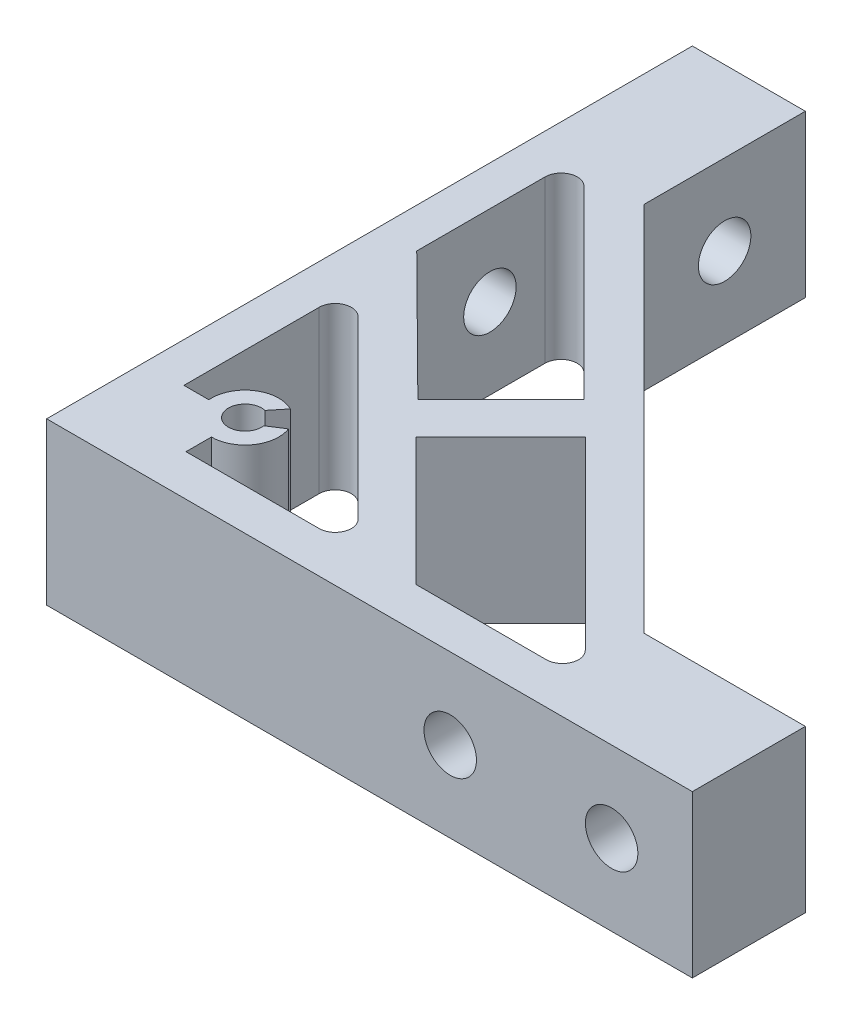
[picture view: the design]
ISO-10303-21;
HEADER;
FILE_DESCRIPTION(('STEP AP214'),'2;1');
FILE_NAME('part.step','',(''),(''),'','','');
FILE_SCHEMA(('AUTOMOTIVE_DESIGN { 1 0 10303 214 1 1 1 1 }'));
ENDSEC;
DATA;
#1=APPLICATION_CONTEXT('core data for automotive mechanical design processes');
#2=APPLICATION_PROTOCOL_DEFINITION('international standard','automotive_design',2000,#1);
#3=PRODUCT_CONTEXT('',#1,'mechanical');
#4=PRODUCT('Part','Part','',(#3));
#5=PRODUCT_RELATED_PRODUCT_CATEGORY('part','',(#4));
#6=PRODUCT_DEFINITION_FORMATION('','',#4);
#7=PRODUCT_DEFINITION_CONTEXT('part definition',#1,'design');
#8=PRODUCT_DEFINITION('design','',#6,#7);
#9=PRODUCT_DEFINITION_SHAPE('','',#8);
#10=(LENGTH_UNIT() NAMED_UNIT(*) SI_UNIT(.MILLI.,.METRE.));
#11=(NAMED_UNIT(*) PLANE_ANGLE_UNIT() SI_UNIT($,.RADIAN.));
#12=(NAMED_UNIT(*) SI_UNIT($,.STERADIAN.) SOLID_ANGLE_UNIT());
#13=UNCERTAINTY_MEASURE_WITH_UNIT(LENGTH_MEASURE(1.E-05),#10,'distance_accuracy_value','');
#14=(GEOMETRIC_REPRESENTATION_CONTEXT(3) GLOBAL_UNCERTAINTY_ASSIGNED_CONTEXT((#13)) GLOBAL_UNIT_ASSIGNED_CONTEXT((#10,
#11,#12)) REPRESENTATION_CONTEXT('',''));
#15=CARTESIAN_POINT('',(0.,0.,0.));
#16=DIRECTION('',(0.,0.,1.));
#17=DIRECTION('',(1.,0.,0.));
#18=AXIS2_PLACEMENT_3D('',#15,#16,#17);
#19=CARTESIAN_POINT('',(50.,10.,-80.));
#20=DIRECTION('',(0.,0.,1.));
#21=DIRECTION('',(1.,0.,0.));
#22=AXIS2_PLACEMENT_3D('',#19,#20,#21);
#23=CYLINDRICAL_SURFACE('',#22,3.25);
#24=CARTESIAN_POINT('',(50.,10.,-5.10542486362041));
#25=DIRECTION('',(0.,0.,1.));
#26=DIRECTION('',(1.,0.,0.));
#27=AXIS2_PLACEMENT_3D('',#24,#25,#26);
#28=CIRCLE('',#27,3.25);
#29=CARTESIAN_POINT('',(53.25,10.,-5.10542486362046));
#30=VERTEX_POINT('',#29);
#31=EDGE_CURVE('E368',#30,#30,#28,.F.);
#32=ORIENTED_EDGE('',*,*,#31,.T.);
#33=EDGE_LOOP('',(#32));
#34=FACE_BOUND('',#33,.T.);
#35=CARTESIAN_POINT('',(50.,10.,0.));
#36=DIRECTION('',(0.,0.,1.));
#37=DIRECTION('',(1.,0.,0.));
#38=AXIS2_PLACEMENT_3D('',#35,#36,#37);
#39=CIRCLE('',#38,3.25);
#40=CARTESIAN_POINT('',(53.25,10.,0.));
#41=VERTEX_POINT('',#40);
#42=EDGE_CURVE('E382',#41,#41,#39,.T.);
#43=ORIENTED_EDGE('',*,*,#42,.T.);
#44=EDGE_LOOP('',(#43));
#45=FACE_BOUND('',#44,.T.);
#46=ADVANCED_FACE('F41',(#34,#45),#23,.F.);
#47=CARTESIAN_POINT('',(14.,20.,-80.));
#48=DIRECTION('',(0.,0.,1.));
#49=DIRECTION('',(1.,0.,0.));
#50=AXIS2_PLACEMENT_3D('',#47,#48,#49);
#51=PLANE('',#50);
#52=DIRECTION('',(-1.,0.,0.));
#53=VECTOR('',#52,1.);
#54=CARTESIAN_POINT('',(14.,0.,-80.));
#55=LINE('',#54,#53);
#56=CARTESIAN_POINT('',(14.,0.,-80.));
#57=VERTEX_POINT('',#56);
#58=CARTESIAN_POINT('',(0.,0.,-80.));
#59=VERTEX_POINT('',#58);
#60=EDGE_CURVE('E408',#57,#59,#55,.T.);
#61=ORIENTED_EDGE('',*,*,#60,.T.);
#62=DIRECTION('',(0.,-1.,0.));
#63=VECTOR('',#62,1.);
#64=CARTESIAN_POINT('',(0.,20.,-80.));
#65=LINE('',#64,#63);
#66=CARTESIAN_POINT('',(0.,20.,-80.));
#67=VERTEX_POINT('',#66);
#68=EDGE_CURVE('E11',#67,#59,#65,.T.);
#69=ORIENTED_EDGE('',*,*,#68,.F.);
#70=DIRECTION('',(-1.,0.,0.));
#71=VECTOR('',#70,1.);
#72=CARTESIAN_POINT('',(14.,20.,-80.));
#73=LINE('',#72,#71);
#74=CARTESIAN_POINT('',(14.,20.,-80.));
#75=VERTEX_POINT('',#74);
#76=EDGE_CURVE('E395',#75,#67,#73,.T.);
#77=ORIENTED_EDGE('',*,*,#76,.F.);
#78=DIRECTION('',(0.,-1.,0.));
#79=VECTOR('',#78,1.);
#80=CARTESIAN_POINT('',(14.,20.,-80.));
#81=LINE('',#80,#79);
#82=EDGE_CURVE('E410',#75,#57,#81,.T.);
#83=ORIENTED_EDGE('',*,*,#82,.T.);
#84=EDGE_LOOP('',(#61,#69,#77,#83));
#85=FACE_BOUND('',#84,.T.);
#86=ADVANCED_FACE('F43',(#85),#51,.F.);
#87=CARTESIAN_POINT('',(0.,20.,-80.));
#88=DIRECTION('',(1.,0.,0.));
#89=DIRECTION('',(0.,0.,-1.));
#90=AXIS2_PLACEMENT_3D('',#87,#88,#89);
#91=PLANE('',#90);
#92=CARTESIAN_POINT('',(0.,9.99999999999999,-70.));
#93=DIRECTION('',(-1.,0.,0.));
#94=DIRECTION('',(0.,0.,1.));
#95=AXIS2_PLACEMENT_3D('',#92,#93,#94);
#96=CIRCLE('',#95,3.25000000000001);
#97=CARTESIAN_POINT('',(0.,9.99999999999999,-66.75));
#98=VERTEX_POINT('',#97);
#99=EDGE_CURVE('E383',#98,#98,#96,.T.);
#100=ORIENTED_EDGE('',*,*,#99,.F.);
#101=EDGE_LOOP('',(#100));
#102=FACE_BOUND('',#101,.T.);
#103=CARTESIAN_POINT('',(0.,9.99999999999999,-50.));
#104=DIRECTION('',(-1.,0.,0.));
#105=DIRECTION('',(0.,0.,1.));
#106=AXIS2_PLACEMENT_3D('',#103,#104,#105);
#107=CIRCLE('',#106,3.25);
#108=CARTESIAN_POINT('',(0.,9.99999999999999,-46.75));
#109=VERTEX_POINT('',#108);
#110=EDGE_CURVE('E388',#109,#109,#107,.T.);
#111=ORIENTED_EDGE('',*,*,#110,.F.);
#112=EDGE_LOOP('',(#111));
#113=FACE_BOUND('',#112,.T.);
#114=DIRECTION('',(0.,0.,1.));
#115=VECTOR('',#114,1.);
#116=CARTESIAN_POINT('',(0.,0.,-80.));
#117=LINE('',#116,#115);
#118=CARTESIAN_POINT('',(0.,0.,0.));
#119=VERTEX_POINT('',#118);
#120=EDGE_CURVE('E415',#59,#119,#117,.T.);
#121=ORIENTED_EDGE('',*,*,#120,.T.);
#122=DIRECTION('',(0.,-1.,0.));
#123=VECTOR('',#122,1.);
#124=CARTESIAN_POINT('',(0.,20.,0.));
#125=LINE('',#124,#123);
#126=CARTESIAN_POINT('',(0.,20.,0.));
#127=VERTEX_POINT('',#126);
#128=EDGE_CURVE('E49',#127,#119,#125,.T.);
#129=ORIENTED_EDGE('',*,*,#128,.F.);
#130=DIRECTION('',(0.,0.,1.));
#131=VECTOR('',#130,1.);
#132=CARTESIAN_POINT('',(0.,20.,-80.));
#133=LINE('',#132,#131);
#134=EDGE_CURVE('E394',#67,#127,#133,.T.);
#135=ORIENTED_EDGE('',*,*,#134,.F.);
#136=ORIENTED_EDGE('',*,*,#68,.T.);
#137=EDGE_LOOP('',(#121,#129,#135,#136));
#138=FACE_BOUND('',#137,.T.);
#139=ADVANCED_FACE('F533',(#102,#113,#138),#91,.F.);
#140=CARTESIAN_POINT('',(0.,20.,0.));
#141=DIRECTION('',(0.,0.,-1.));
#142=DIRECTION('',(-1.,0.,0.));
#143=AXIS2_PLACEMENT_3D('',#140,#141,#142);
#144=PLANE('',#143);
#145=CARTESIAN_POINT('',(70.,10.,0.));
#146=DIRECTION('',(0.,0.,1.));
#147=DIRECTION('',(1.,0.,0.));
#148=AXIS2_PLACEMENT_3D('',#145,#146,#147);
#149=CIRCLE('',#148,3.25000000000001);
#150=CARTESIAN_POINT('',(73.25,10.,0.));
#151=VERTEX_POINT('',#150);
#152=EDGE_CURVE('E380',#151,#151,#149,.T.);
#153=ORIENTED_EDGE('',*,*,#152,.F.);
#154=EDGE_LOOP('',(#153));
#155=FACE_BOUND('',#154,.T.);
#156=ORIENTED_EDGE('',*,*,#42,.F.);
#157=EDGE_LOOP('',(#156));
#158=FACE_BOUND('',#157,.T.);
#159=DIRECTION('',(1.,0.,0.));
#160=VECTOR('',#159,1.);
#161=CARTESIAN_POINT('',(0.,0.,0.));
#162=LINE('',#161,#160);
#163=CARTESIAN_POINT('',(80.,0.,0.));
#164=VERTEX_POINT('',#163);
#165=EDGE_CURVE('E413',#119,#164,#162,.T.);
#166=ORIENTED_EDGE('',*,*,#165,.T.);
#167=DIRECTION('',(0.,-1.,0.));
#168=VECTOR('',#167,1.);
#169=CARTESIAN_POINT('',(80.,20.,0.));
#170=LINE('',#169,#168);
#171=CARTESIAN_POINT('',(80.,20.,0.));
#172=VERTEX_POINT('',#171);
#173=EDGE_CURVE('E432',#172,#164,#170,.T.);
#174=ORIENTED_EDGE('',*,*,#173,.F.);
#175=DIRECTION('',(1.,0.,0.));
#176=VECTOR('',#175,1.);
#177=CARTESIAN_POINT('',(0.,20.,0.));
#178=LINE('',#177,#176);
#179=EDGE_CURVE('E400',#127,#172,#178,.T.);
#180=ORIENTED_EDGE('',*,*,#179,.F.);
#181=ORIENTED_EDGE('',*,*,#128,.T.);
#182=EDGE_LOOP('',(#166,#174,#180,#181));
#183=FACE_BOUND('',#182,.T.);
#184=ADVANCED_FACE('F567',(#155,#158,#183),#144,.F.);
#185=CARTESIAN_POINT('',(80.,20.,0.));
#186=DIRECTION('',(-1.,0.,0.));
#187=DIRECTION('',(0.,0.,1.));
#188=AXIS2_PLACEMENT_3D('',#185,#186,#187);
#189=PLANE('',#188);
#190=DIRECTION('',(0.,0.,-1.));
#191=VECTOR('',#190,1.);
#192=CARTESIAN_POINT('',(80.,0.,0.));
#193=LINE('',#192,#191);
#194=CARTESIAN_POINT('',(80.,0.,-14.));
#195=VERTEX_POINT('',#194);
#196=EDGE_CURVE('E417',#164,#195,#193,.T.);
#197=ORIENTED_EDGE('',*,*,#196,.T.);
#198=DIRECTION('',(0.,-1.,0.));
#199=VECTOR('',#198,1.);
#200=CARTESIAN_POINT('',(80.,20.,-14.));
#201=LINE('',#200,#199);
#202=CARTESIAN_POINT('',(80.,20.,-14.));
#203=VERTEX_POINT('',#202);
#204=EDGE_CURVE('E431',#203,#195,#201,.T.);
#205=ORIENTED_EDGE('',*,*,#204,.F.);
#206=DIRECTION('',(0.,0.,-1.));
#207=VECTOR('',#206,1.);
#208=CARTESIAN_POINT('',(80.,20.,0.));
#209=LINE('',#208,#207);
#210=EDGE_CURVE('E398',#172,#203,#209,.T.);
#211=ORIENTED_EDGE('',*,*,#210,.F.);
#212=ORIENTED_EDGE('',*,*,#173,.T.);
#213=EDGE_LOOP('',(#197,#205,#211,#212));
#214=FACE_BOUND('',#213,.T.);
#215=ADVANCED_FACE('F564',(#214),#189,.F.);
#216=CARTESIAN_POINT('',(80.,20.,-14.));
#217=DIRECTION('',(0.,0.,1.));
#218=DIRECTION('',(1.,0.,0.));
#219=AXIS2_PLACEMENT_3D('',#216,#217,#218);
#220=PLANE('',#219);
#221=CARTESIAN_POINT('',(70.,10.,-14.));
#222=DIRECTION('',(0.,0.,1.));
#223=DIRECTION('',(1.,0.,0.));
#224=AXIS2_PLACEMENT_3D('',#221,#222,#223);
#225=CIRCLE('',#224,3.25000000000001);
#226=CARTESIAN_POINT('',(73.25,10.,-14.));
#227=VERTEX_POINT('',#226);
#228=EDGE_CURVE('E379',#227,#227,#225,.T.);
#229=ORIENTED_EDGE('',*,*,#228,.T.);
#230=EDGE_LOOP('',(#229));
#231=FACE_BOUND('',#230,.T.);
#232=DIRECTION('',(-1.,0.,0.));
#233=VECTOR('',#232,1.);
#234=CARTESIAN_POINT('',(80.,0.,-14.));
#235=LINE('',#234,#233);
#236=CARTESIAN_POINT('',(60.,0.,-14.));
#237=VERTEX_POINT('',#236);
#238=EDGE_CURVE('E420',#195,#237,#235,.T.);
#239=ORIENTED_EDGE('',*,*,#238,.T.);
#240=DIRECTION('',(0.,-1.,0.));
#241=VECTOR('',#240,1.);
#242=CARTESIAN_POINT('',(60.,20.,-14.));
#243=LINE('',#242,#241);
#244=CARTESIAN_POINT('',(60.,20.,-14.));
#245=VERTEX_POINT('',#244);
#246=EDGE_CURVE('E426',#245,#237,#243,.T.);
#247=ORIENTED_EDGE('',*,*,#246,.F.);
#248=DIRECTION('',(-1.,0.,0.));
#249=VECTOR('',#248,1.);
#250=CARTESIAN_POINT('',(80.,20.,-14.));
#251=LINE('',#250,#249);
#252=EDGE_CURVE('E405',#203,#245,#251,.T.);
#253=ORIENTED_EDGE('',*,*,#252,.F.);
#254=ORIENTED_EDGE('',*,*,#204,.T.);
#255=EDGE_LOOP('',(#239,#247,#253,#254));
#256=FACE_BOUND('',#255,.T.);
#257=ADVANCED_FACE('F565',(#231,#256),#220,.F.);
#258=CARTESIAN_POINT('',(60.,20.,-14.));
#259=DIRECTION('',(-0.707106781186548,0.,0.707106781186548));
#260=DIRECTION('',(0.707106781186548,0.,0.707106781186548));
#261=AXIS2_PLACEMENT_3D('',#258,#259,#260);
#262=PLANE('',#261);
#263=CARTESIAN_POINT('',(24.,9.99999999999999,-50.));
#264=DIRECTION('',(-0.707106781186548,0.,0.707106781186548));
#265=DIRECTION('',(0.707106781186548,0.,0.707106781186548));
#266=AXIS2_PLACEMENT_3D('',#263,#264,#265);
#267=ELLIPSE('',#266,7.77817459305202,5.5);
#268=CARTESIAN_POINT('',(29.5,9.99999999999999,-44.5));
#269=VERTEX_POINT('',#268);
#270=EDGE_CURVE('E449',#269,#269,#267,.T.);
#271=ORIENTED_EDGE('',*,*,#270,.T.);
#272=EDGE_LOOP('',(#271));
#273=FACE_BOUND('',#272,.T.);
#274=CARTESIAN_POINT('',(50.,10.,-24.));
#275=DIRECTION('',(-0.707106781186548,0.,0.707106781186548));
#276=DIRECTION('',(-0.707106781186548,0.,-0.707106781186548));
#277=AXIS2_PLACEMENT_3D('',#274,#275,#276);
#278=ELLIPSE('',#277,7.77817459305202,5.5);
#279=CARTESIAN_POINT('',(44.5,10.,-29.5));
#280=VERTEX_POINT('',#279);
#281=EDGE_CURVE('E244',#280,#280,#278,.F.);
#282=ORIENTED_EDGE('',*,*,#281,.F.);
#283=EDGE_LOOP('',(#282));
#284=FACE_BOUND('',#283,.T.);
#285=DIRECTION('',(-0.707106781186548,0.,-0.707106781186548));
#286=VECTOR('',#285,1.);
#287=CARTESIAN_POINT('',(60.,0.,-14.));
#288=LINE('',#287,#286);
#289=CARTESIAN_POINT('',(14.,0.,-60.));
#290=VERTEX_POINT('',#289);
#291=EDGE_CURVE('E418',#237,#290,#288,.T.);
#292=ORIENTED_EDGE('',*,*,#291,.T.);
#293=DIRECTION('',(0.,-1.,0.));
#294=VECTOR('',#293,1.);
#295=CARTESIAN_POINT('',(14.,20.,-60.));
#296=LINE('',#295,#294);
#297=CARTESIAN_POINT('',(14.,20.,-60.));
#298=VERTEX_POINT('',#297);
#299=EDGE_CURVE('E424',#298,#290,#296,.T.);
#300=ORIENTED_EDGE('',*,*,#299,.F.);
#301=DIRECTION('',(-0.707106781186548,0.,-0.707106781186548));
#302=VECTOR('',#301,1.);
#303=CARTESIAN_POINT('',(60.,20.,-14.));
#304=LINE('',#303,#302);
#305=EDGE_CURVE('E404',#245,#298,#304,.T.);
#306=ORIENTED_EDGE('',*,*,#305,.F.);
#307=ORIENTED_EDGE('',*,*,#246,.T.);
#308=EDGE_LOOP('',(#292,#300,#306,#307));
#309=FACE_BOUND('',#308,.T.);
#310=ADVANCED_FACE('F556',(#273,#284,#309),#262,.F.);
#311=CARTESIAN_POINT('',(14.,20.,-60.));
#312=DIRECTION('',(-1.,0.,0.));
#313=DIRECTION('',(0.,0.,1.));
#314=AXIS2_PLACEMENT_3D('',#311,#312,#313);
#315=PLANE('',#314);
#316=CARTESIAN_POINT('',(14.,9.99999999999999,-70.));
#317=DIRECTION('',(-1.,0.,0.));
#318=DIRECTION('',(0.,0.,1.));
#319=AXIS2_PLACEMENT_3D('',#316,#317,#318);
#320=CIRCLE('',#319,3.25000000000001);
#321=CARTESIAN_POINT('',(14.,9.99999999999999,-66.75));
#322=VERTEX_POINT('',#321);
#323=EDGE_CURVE('E390',#322,#322,#320,.T.);
#324=ORIENTED_EDGE('',*,*,#323,.T.);
#325=EDGE_LOOP('',(#324));
#326=FACE_BOUND('',#325,.T.);
#327=DIRECTION('',(0.,0.,-1.));
#328=VECTOR('',#327,1.);
#329=CARTESIAN_POINT('',(14.,0.,-60.));
#330=LINE('',#329,#328);
#331=EDGE_CURVE('E397',#290,#57,#330,.T.);
#332=ORIENTED_EDGE('',*,*,#331,.T.);
#333=ORIENTED_EDGE('',*,*,#82,.F.);
#334=DIRECTION('',(0.,0.,-1.));
#335=VECTOR('',#334,1.);
#336=CARTESIAN_POINT('',(14.,20.,-60.));
#337=LINE('',#336,#335);
#338=EDGE_CURVE('E409',#298,#75,#337,.T.);
#339=ORIENTED_EDGE('',*,*,#338,.F.);
#340=ORIENTED_EDGE('',*,*,#299,.T.);
#341=EDGE_LOOP('',(#332,#333,#339,#340));
#342=FACE_BOUND('',#341,.T.);
#343=ADVANCED_FACE('F553',(#326,#342),#315,.F.);
#344=CARTESIAN_POINT('',(0.,20.,0.));
#345=DIRECTION('',(0.,1.,0.));
#346=DIRECTION('',(0.,0.,1.));
#347=AXIS2_PLACEMENT_3D('',#344,#345,#346);
#348=PLANE('',#347);
#349=DIRECTION('',(-0.707106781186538,0.,-0.707106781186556));
#350=VECTOR('',#349,1.);
#351=CARTESIAN_POINT('',(40.6627812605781,20.,-5.10542486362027));
#352=LINE('',#351,#350);
#353=CARTESIAN_POINT('',(40.6627812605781,20.,-5.10542486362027));
#354=VERTEX_POINT('',#353);
#355=CARTESIAN_POINT('',(24.8379244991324,20.,-20.9302816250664));
#356=VERTEX_POINT('',#355);
#357=EDGE_CURVE('E313',#354,#356,#352,.T.);
#358=ORIENTED_EDGE('',*,*,#357,.T.);
#359=DIRECTION('',(0.707106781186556,0.,-0.707106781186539));
#360=VECTOR('',#359,1.);
#361=CARTESIAN_POINT('',(24.8379244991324,20.,-20.9302816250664));
#362=LINE('',#361,#360);
#363=CARTESIAN_POINT('',(35.3190252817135,20.,-31.4113824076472));
#364=VERTEX_POINT('',#363);
#365=EDGE_CURVE('E334',#356,#364,#362,.T.);
#366=ORIENTED_EDGE('',*,*,#365,.T.);
#367=DIRECTION('',(0.707106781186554,0.,0.707106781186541));
#368=VECTOR('',#367,1.);
#369=CARTESIAN_POINT('',(35.3190252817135,20.,-31.4113824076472));
#370=LINE('',#369,#368);
#371=CARTESIAN_POINT('',(58.2107692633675,20.,-8.51963842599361));
#372=VERTEX_POINT('',#371);
#373=EDGE_CURVE('E59',#364,#372,#370,.T.);
#374=ORIENTED_EDGE('',*,*,#373,.T.);
#375=CARTESIAN_POINT('',(56.7965557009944,20.,-7.10542486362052));
#376=DIRECTION('',(0.,-1.,0.));
#377=DIRECTION('',(0.,0.,-1.));
#378=AXIS2_PLACEMENT_3D('',#375,#376,#377);
#379=CIRCLE('',#378,2.);
#380=CARTESIAN_POINT('',(56.7965557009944,20.,-5.10542486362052));
#381=VERTEX_POINT('',#380);
#382=EDGE_CURVE('E327',#372,#381,#379,.T.);
#383=ORIENTED_EDGE('',*,*,#382,.T.);
#384=DIRECTION('',(-1.,0.,0.));
#385=VECTOR('',#384,1.);
#386=CARTESIAN_POINT('',(56.7965557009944,20.,-5.10542486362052));
#387=LINE('',#386,#385);
#388=EDGE_CURVE('E302',#381,#354,#387,.T.);
#389=ORIENTED_EDGE('',*,*,#388,.T.);
#390=EDGE_LOOP('',(#358,#366,#374,#383,#389));
#391=FACE_BOUND('',#390,.T.);
#392=DIRECTION('',(0.,0.,-1.));
#393=VECTOR('',#392,1.);
#394=CARTESIAN_POINT('',(12.1608269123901,20.,-5.10542486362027));
#395=LINE('',#394,#393);
#396=CARTESIAN_POINT('',(12.1608269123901,20.,-5.10542486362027));
#397=VERTEX_POINT('',#396);
#398=CARTESIAN_POINT('',(12.1608269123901,20.,-8.24916747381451));
#399=VERTEX_POINT('',#398);
#400=EDGE_CURVE('E239',#397,#399,#395,.T.);
#401=ORIENTED_EDGE('',*,*,#400,.T.);
#402=CARTESIAN_POINT('',(12.1608269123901,20.,-12.4227167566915));
#403=DIRECTION('',(0.,1.,0.));
#404=DIRECTION('',(0.,0.,-1.));
#405=AXIS2_PLACEMENT_3D('',#402,#403,#404);
#406=CIRCLE('',#405,4.17354928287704);
#407=CARTESIAN_POINT('',(16.0655128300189,20.,-13.8964675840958));
#408=VERTEX_POINT('',#407);
#409=EDGE_CURVE('E300',#399,#408,#406,.T.);
#410=ORIENTED_EDGE('',*,*,#409,.T.);
#411=DIRECTION('',(-0.841480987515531,0.,0.540286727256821));
#412=VECTOR('',#411,1.);
#413=CARTESIAN_POINT('',(16.0655128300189,20.,-13.8964675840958));
#414=LINE('',#413,#412);
#415=CARTESIAN_POINT('',(14.2026570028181,20.,-12.7003903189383));
#416=VERTEX_POINT('',#415);
#417=EDGE_CURVE('E66',#408,#416,#414,.T.);
#418=ORIENTED_EDGE('',*,*,#417,.T.);
#419=CARTESIAN_POINT('',(12.1608269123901,20.,-12.4227167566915));
#420=DIRECTION('',(0.,-1.,0.));
#421=DIRECTION('',(0.,0.,-1.));
#422=AXIS2_PLACEMENT_3D('',#419,#420,#421);
#423=CIRCLE('',#422,2.06062435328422);
#424=CARTESIAN_POINT('',(12.6254849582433,20.,-14.4302689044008));
#425=VERTEX_POINT('',#424);
#426=EDGE_CURVE('E291',#416,#425,#423,.T.);
#427=ORIENTED_EDGE('',*,*,#426,.T.);
#428=DIRECTION('',(0.631646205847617,0.,-0.775256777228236));
#429=VECTOR('',#428,1.);
#430=CARTESIAN_POINT('',(12.6254849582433,20.,-14.4302689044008));
#431=LINE('',#430,#429);
#432=CARTESIAN_POINT('',(14.030107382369,20.,-16.1542451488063));
#433=VERTEX_POINT('',#432);
#434=EDGE_CURVE('E288',#425,#433,#431,.T.);
#435=ORIENTED_EDGE('',*,*,#434,.T.);
#436=CARTESIAN_POINT('',(12.1608269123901,20.,-12.4227167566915));
#437=DIRECTION('',(0.,1.,0.));
#438=DIRECTION('',(0.,0.,-1.));
#439=AXIS2_PLACEMENT_3D('',#436,#437,#438);
#440=CIRCLE('',#439,4.17354928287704);
#441=CARTESIAN_POINT('',(8.00052028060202,20.,-12.0905084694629));
#442=VERTEX_POINT('',#441);
#443=EDGE_CURVE('E289',#433,#442,#440,.T.);
#444=ORIENTED_EDGE('',*,*,#443,.T.);
#445=DIRECTION('',(-1.,0.,0.));
#446=VECTOR('',#445,1.);
#447=CARTESIAN_POINT('',(4.91656822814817,20.,-12.0905084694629));
#448=LINE('',#447,#446);
#449=CARTESIAN_POINT('',(4.91656822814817,20.,-12.0905084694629));
#450=VERTEX_POINT('',#449);
#451=EDGE_CURVE('E283',#442,#450,#448,.T.);
#452=ORIENTED_EDGE('',*,*,#451,.T.);
#453=DIRECTION('',(0.,0.,-1.));
#454=VECTOR('',#453,1.);
#455=CARTESIAN_POINT('',(4.91656822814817,20.,-28.8402167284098));
#456=LINE('',#455,#454);
#457=CARTESIAN_POINT('',(4.91656822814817,20.,-28.8402167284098));
#458=VERTEX_POINT('',#457);
#459=EDGE_CURVE('E281',#450,#458,#456,.T.);
#460=ORIENTED_EDGE('',*,*,#459,.T.);
#461=CARTESIAN_POINT('',(6.91656822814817,20.,-28.8402167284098));
#462=DIRECTION('',(0.,-1.,0.));
#463=DIRECTION('',(0.,0.,1.));
#464=AXIS2_PLACEMENT_3D('',#461,#462,#463);
#465=CIRCLE('',#464,2.);
#466=CARTESIAN_POINT('',(8.33078179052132,20.,-30.2544302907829));
#467=VERTEX_POINT('',#466);
#468=EDGE_CURVE('E280',#458,#467,#465,.T.);
#469=ORIENTED_EDGE('',*,*,#468,.T.);
#470=DIRECTION('',(0.707106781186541,0.,0.707106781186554));
#471=VECTOR('',#470,1.);
#472=CARTESIAN_POINT('',(30.0655736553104,20.,-8.51963842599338));
#473=LINE('',#472,#471);
#474=CARTESIAN_POINT('',(30.0655736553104,20.,-8.51963842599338));
#475=VERTEX_POINT('',#474);
#476=EDGE_CURVE('E273',#467,#475,#473,.T.);
#477=ORIENTED_EDGE('',*,*,#476,.T.);
#478=CARTESIAN_POINT('',(28.6513600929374,20.,-7.10542486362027));
#479=DIRECTION('',(0.,-1.,0.));
#480=DIRECTION('',(0.,0.,1.));
#481=AXIS2_PLACEMENT_3D('',#478,#479,#480);
#482=CIRCLE('',#481,2.);
#483=CARTESIAN_POINT('',(28.6513600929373,20.,-5.10542486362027));
#484=VERTEX_POINT('',#483);
#485=EDGE_CURVE('E272',#475,#484,#482,.T.);
#486=ORIENTED_EDGE('',*,*,#485,.T.);
#487=DIRECTION('',(-1.,0.,0.));
#488=VECTOR('',#487,1.);
#489=CARTESIAN_POINT('',(12.1608269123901,20.,-5.10542486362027));
#490=LINE('',#489,#488);
#491=EDGE_CURVE('E266',#484,#397,#490,.T.);
#492=ORIENTED_EDGE('',*,*,#491,.T.);
#493=EDGE_LOOP('',(#401,#410,#418,#427,#435,#444,#452,#460,#469,#477,#486,#492));
#494=FACE_BOUND('',#493,.T.);
#495=DIRECTION('',(-0.710210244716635,0.,-0.703989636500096));
#496=VECTOR('',#495,1.);
#497=CARTESIAN_POINT('',(4.91656822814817,20.,-40.9348925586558));
#498=LINE('',#497,#496);
#499=CARTESIAN_POINT('',(20.90108039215,20.,-25.0903859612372));
#500=VERTEX_POINT('',#499);
#501=CARTESIAN_POINT('',(4.91656822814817,20.,-40.9348925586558));
#502=VERTEX_POINT('',#501);
#503=EDGE_CURVE('E340',#500,#502,#498,.T.);
#504=ORIENTED_EDGE('',*,*,#503,.T.);
#505=DIRECTION('',(0.,0.,-1.));
#506=VECTOR('',#505,1.);
#507=CARTESIAN_POINT('',(4.91656822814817,20.,-56.8281788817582));
#508=LINE('',#507,#506);
#509=CARTESIAN_POINT('',(4.91656822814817,20.,-56.8281788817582));
#510=VERTEX_POINT('',#509);
#511=EDGE_CURVE('E338',#502,#510,#508,.T.);
#512=ORIENTED_EDGE('',*,*,#511,.T.);
#513=CARTESIAN_POINT('',(6.91656822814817,20.,-56.8281788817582));
#514=DIRECTION('',(0.,-1.,0.));
#515=DIRECTION('',(0.,0.,1.));
#516=AXIS2_PLACEMENT_3D('',#513,#514,#515);
#517=CIRCLE('',#516,2.);
#518=CARTESIAN_POINT('',(8.33078179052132,20.,-58.2423924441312));
#519=VERTEX_POINT('',#518);
#520=EDGE_CURVE('E343',#510,#519,#517,.T.);
#521=ORIENTED_EDGE('',*,*,#520,.T.);
#522=DIRECTION('',(0.707106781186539,0.,0.707106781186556));
#523=VECTOR('',#522,1.);
#524=CARTESIAN_POINT('',(31.1919343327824,20.,-35.3812399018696));
#525=LINE('',#524,#523);
#526=CARTESIAN_POINT('',(31.1919343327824,20.,-35.3812399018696));
#527=VERTEX_POINT('',#526);
#528=EDGE_CURVE('E350',#519,#527,#525,.T.);
#529=ORIENTED_EDGE('',*,*,#528,.T.);
#530=DIRECTION('',(-0.707106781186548,0.,0.707106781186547));
#531=VECTOR('',#530,1.);
#532=CARTESIAN_POINT('',(20.90108039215,20.,-25.0903859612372));
#533=LINE('',#532,#531);
#534=EDGE_CURVE('E349',#527,#500,#533,.T.);
#535=ORIENTED_EDGE('',*,*,#534,.T.);
#536=EDGE_LOOP('',(#504,#512,#521,#529,#535));
#537=FACE_BOUND('',#536,.T.);
#538=ORIENTED_EDGE('',*,*,#76,.T.);
#539=ORIENTED_EDGE('',*,*,#134,.T.);
#540=ORIENTED_EDGE('',*,*,#179,.T.);
#541=ORIENTED_EDGE('',*,*,#210,.T.);
#542=ORIENTED_EDGE('',*,*,#252,.T.);
#543=ORIENTED_EDGE('',*,*,#305,.T.);
#544=ORIENTED_EDGE('',*,*,#338,.T.);
#545=EDGE_LOOP('',(#538,#539,#540,#541,#542,#543,#544));
#546=FACE_BOUND('',#545,.T.);
#547=ADVANCED_FACE('F509',(#391,#494,#537,#546),#348,.T.);
#548=CARTESIAN_POINT('',(0.,0.,0.));
#549=DIRECTION('',(0.,1.,0.));
#550=DIRECTION('',(0.,0.,1.));
#551=AXIS2_PLACEMENT_3D('',#548,#549,#550);
#552=PLANE('',#551);
#553=DIRECTION('',(0.707106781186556,0.,-0.707106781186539));
#554=VECTOR('',#553,1.);
#555=CARTESIAN_POINT('',(24.8379244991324,0.,-20.9302816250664));
#556=LINE('',#555,#554);
#557=CARTESIAN_POINT('',(24.8379244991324,0.,-20.9302816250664));
#558=VERTEX_POINT('',#557);
#559=CARTESIAN_POINT('',(35.3190252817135,0.,-31.4113824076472));
#560=VERTEX_POINT('',#559);
#561=EDGE_CURVE('E318',#558,#560,#556,.T.);
#562=ORIENTED_EDGE('',*,*,#561,.F.);
#563=DIRECTION('',(-0.707106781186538,0.,-0.707106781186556));
#564=VECTOR('',#563,1.);
#565=CARTESIAN_POINT('',(40.6627812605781,0.,-5.10542486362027));
#566=LINE('',#565,#564);
#567=CARTESIAN_POINT('',(40.6627812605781,0.,-5.10542486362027));
#568=VERTEX_POINT('',#567);
#569=EDGE_CURVE('E325',#568,#558,#566,.T.);
#570=ORIENTED_EDGE('',*,*,#569,.F.);
#571=DIRECTION('',(-1.,0.,0.));
#572=VECTOR('',#571,1.);
#573=CARTESIAN_POINT('',(56.7965557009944,0.,-5.10542486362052));
#574=LINE('',#573,#572);
#575=CARTESIAN_POINT('',(56.7965557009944,0.,-5.10542486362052));
#576=VERTEX_POINT('',#575);
#577=EDGE_CURVE('E309',#576,#568,#574,.T.);
#578=ORIENTED_EDGE('',*,*,#577,.F.);
#579=CARTESIAN_POINT('',(56.7965557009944,0.,-7.10542486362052));
#580=DIRECTION('',(0.,-1.,0.));
#581=DIRECTION('',(0.,0.,-1.));
#582=AXIS2_PLACEMENT_3D('',#579,#580,#581);
#583=CIRCLE('',#582,2.);
#584=CARTESIAN_POINT('',(58.2107692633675,0.,-8.51963842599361));
#585=VERTEX_POINT('',#584);
#586=EDGE_CURVE('E312',#585,#576,#583,.T.);
#587=ORIENTED_EDGE('',*,*,#586,.F.);
#588=DIRECTION('',(0.707106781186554,0.,0.707106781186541));
#589=VECTOR('',#588,1.);
#590=CARTESIAN_POINT('',(35.3190252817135,0.,-31.4113824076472));
#591=LINE('',#590,#589);
#592=EDGE_CURVE('E320',#560,#585,#591,.T.);
#593=ORIENTED_EDGE('',*,*,#592,.F.);
#594=EDGE_LOOP('',(#562,#570,#578,#587,#593));
#595=FACE_BOUND('',#594,.T.);
#596=CARTESIAN_POINT('',(12.1608269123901,0.,-12.4227167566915));
#597=DIRECTION('',(0.,1.,0.));
#598=DIRECTION('',(0.,0.,-1.));
#599=AXIS2_PLACEMENT_3D('',#596,#597,#598);
#600=CIRCLE('',#599,4.17354928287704);
#601=CARTESIAN_POINT('',(12.1608269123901,0.,-8.24916747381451));
#602=VERTEX_POINT('',#601);
#603=CARTESIAN_POINT('',(16.0655128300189,0.,-13.8964675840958));
#604=VERTEX_POINT('',#603);
#605=EDGE_CURVE('E257',#602,#604,#600,.T.);
#606=ORIENTED_EDGE('',*,*,#605,.F.);
#607=DIRECTION('',(0.,0.,-1.));
#608=VECTOR('',#607,1.);
#609=CARTESIAN_POINT('',(12.1608269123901,0.,-5.10542486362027));
#610=LINE('',#609,#608);
#611=CARTESIAN_POINT('',(12.1608269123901,0.,-5.10542486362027));
#612=VERTEX_POINT('',#611);
#613=EDGE_CURVE('E240',#612,#602,#610,.T.);
#614=ORIENTED_EDGE('',*,*,#613,.F.);
#615=DIRECTION('',(-1.,0.,0.));
#616=VECTOR('',#615,1.);
#617=CARTESIAN_POINT('',(12.1608269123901,0.,-5.10542486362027));
#618=LINE('',#617,#616);
#619=CARTESIAN_POINT('',(28.6513600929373,0.,-5.10542486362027));
#620=VERTEX_POINT('',#619);
#621=EDGE_CURVE('E247',#620,#612,#618,.T.);
#622=ORIENTED_EDGE('',*,*,#621,.F.);
#623=CARTESIAN_POINT('',(28.6513600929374,0.,-7.10542486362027));
#624=DIRECTION('',(0.,-1.,0.));
#625=DIRECTION('',(0.,0.,1.));
#626=AXIS2_PLACEMENT_3D('',#623,#624,#625);
#627=CIRCLE('',#626,2.);
#628=CARTESIAN_POINT('',(30.0655736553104,0.,-8.51963842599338));
#629=VERTEX_POINT('',#628);
#630=EDGE_CURVE('E254',#629,#620,#627,.T.);
#631=ORIENTED_EDGE('',*,*,#630,.F.);
#632=DIRECTION('',(0.707106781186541,0.,0.707106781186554));
#633=VECTOR('',#632,1.);
#634=CARTESIAN_POINT('',(30.0655736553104,0.,-8.51963842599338));
#635=LINE('',#634,#633);
#636=CARTESIAN_POINT('',(8.33078179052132,0.,-30.2544302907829));
#637=VERTEX_POINT('',#636);
#638=EDGE_CURVE('E479',#637,#629,#635,.T.);
#639=ORIENTED_EDGE('',*,*,#638,.F.);
#640=CARTESIAN_POINT('',(6.91656822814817,0.,-28.8402167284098));
#641=DIRECTION('',(0.,-1.,0.));
#642=DIRECTION('',(0.,0.,1.));
#643=AXIS2_PLACEMENT_3D('',#640,#641,#642);
#644=CIRCLE('',#643,2.);
#645=CARTESIAN_POINT('',(4.91656822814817,0.,-28.8402167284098));
#646=VERTEX_POINT('',#645);
#647=EDGE_CURVE('E485',#646,#637,#644,.T.);
#648=ORIENTED_EDGE('',*,*,#647,.F.);
#649=DIRECTION('',(0.,0.,-1.));
#650=VECTOR('',#649,1.);
#651=CARTESIAN_POINT('',(4.91656822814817,0.,-28.8402167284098));
#652=LINE('',#651,#650);
#653=CARTESIAN_POINT('',(4.91656822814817,0.,-12.0905084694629));
#654=VERTEX_POINT('',#653);
#655=EDGE_CURVE('E488',#654,#646,#652,.T.);
#656=ORIENTED_EDGE('',*,*,#655,.F.);
#657=DIRECTION('',(-1.,0.,0.));
#658=VECTOR('',#657,1.);
#659=CARTESIAN_POINT('',(4.91656822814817,0.,-12.0905084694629));
#660=LINE('',#659,#658);
#661=CARTESIAN_POINT('',(8.00052028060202,0.,-12.0905084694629));
#662=VERTEX_POINT('',#661);
#663=EDGE_CURVE('E490',#662,#654,#660,.T.);
#664=ORIENTED_EDGE('',*,*,#663,.F.);
#665=CARTESIAN_POINT('',(12.1608269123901,0.,-12.4227167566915));
#666=DIRECTION('',(0.,1.,0.));
#667=DIRECTION('',(0.,0.,-1.));
#668=AXIS2_PLACEMENT_3D('',#665,#666,#667);
#669=CIRCLE('',#668,4.17354928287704);
#670=CARTESIAN_POINT('',(14.030107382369,0.,-16.1542451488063));
#671=VERTEX_POINT('',#670);
#672=EDGE_CURVE('E495',#671,#662,#669,.T.);
#673=ORIENTED_EDGE('',*,*,#672,.F.);
#674=DIRECTION('',(0.631646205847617,0.,-0.775256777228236));
#675=VECTOR('',#674,1.);
#676=CARTESIAN_POINT('',(12.6254849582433,0.,-14.4302689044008));
#677=LINE('',#676,#675);
#678=CARTESIAN_POINT('',(12.6254849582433,0.,-14.4302689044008));
#679=VERTEX_POINT('',#678);
#680=EDGE_CURVE('E492',#679,#671,#677,.T.);
#681=ORIENTED_EDGE('',*,*,#680,.F.);
#682=CARTESIAN_POINT('',(12.1608269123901,0.,-12.4227167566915));
#683=DIRECTION('',(0.,-1.,0.));
#684=DIRECTION('',(0.,0.,-1.));
#685=AXIS2_PLACEMENT_3D('',#682,#683,#684);
#686=CIRCLE('',#685,2.06062435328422);
#687=CARTESIAN_POINT('',(14.2026570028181,0.,-12.7003903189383));
#688=VERTEX_POINT('',#687);
#689=EDGE_CURVE('E498',#688,#679,#686,.T.);
#690=ORIENTED_EDGE('',*,*,#689,.F.);
#691=DIRECTION('',(-0.841480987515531,0.,0.540286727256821));
#692=VECTOR('',#691,1.);
#693=CARTESIAN_POINT('',(16.0655128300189,0.,-13.8964675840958));
#694=LINE('',#693,#692);
#695=EDGE_CURVE('E264',#604,#688,#694,.T.);
#696=ORIENTED_EDGE('',*,*,#695,.F.);
#697=EDGE_LOOP('',(#606,#614,#622,#631,#639,#648,#656,#664,#673,#681,#690,#696));
#698=FACE_BOUND('',#697,.T.);
#699=DIRECTION('',(0.,0.,-1.));
#700=VECTOR('',#699,1.);
#701=CARTESIAN_POINT('',(4.91656822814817,0.,-56.8281788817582));
#702=LINE('',#701,#700);
#703=CARTESIAN_POINT('',(4.91656822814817,0.,-40.9348925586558));
#704=VERTEX_POINT('',#703);
#705=CARTESIAN_POINT('',(4.91656822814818,0.,-56.8281788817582));
#706=VERTEX_POINT('',#705);
#707=EDGE_CURVE('E353',#704,#706,#702,.T.);
#708=ORIENTED_EDGE('',*,*,#707,.F.);
#709=DIRECTION('',(-0.710210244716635,0.,-0.703989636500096));
#710=VECTOR('',#709,1.);
#711=CARTESIAN_POINT('',(4.91656822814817,0.,-40.9348925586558));
#712=LINE('',#711,#710);
#713=CARTESIAN_POINT('',(20.90108039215,0.,-25.0903859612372));
#714=VERTEX_POINT('',#713);
#715=EDGE_CURVE('E322',#714,#704,#712,.T.);
#716=ORIENTED_EDGE('',*,*,#715,.F.);
#717=DIRECTION('',(-0.707106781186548,0.,0.707106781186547));
#718=VECTOR('',#717,1.);
#719=CARTESIAN_POINT('',(20.90108039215,0.,-25.0903859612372));
#720=LINE('',#719,#718);
#721=CARTESIAN_POINT('',(31.1919343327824,0.,-35.3812399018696));
#722=VERTEX_POINT('',#721);
#723=EDGE_CURVE('E344',#722,#714,#720,.T.);
#724=ORIENTED_EDGE('',*,*,#723,.F.);
#725=DIRECTION('',(0.707106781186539,0.,0.707106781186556));
#726=VECTOR('',#725,1.);
#727=CARTESIAN_POINT('',(31.1919343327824,0.,-35.3812399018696));
#728=LINE('',#727,#726);
#729=CARTESIAN_POINT('',(8.33078179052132,0.,-58.2423924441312));
#730=VERTEX_POINT('',#729);
#731=EDGE_CURVE('E363',#730,#722,#728,.T.);
#732=ORIENTED_EDGE('',*,*,#731,.F.);
#733=CARTESIAN_POINT('',(6.91656822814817,0.,-56.8281788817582));
#734=DIRECTION('',(0.,-1.,0.));
#735=DIRECTION('',(0.,0.,1.));
#736=AXIS2_PLACEMENT_3D('',#733,#734,#735);
#737=CIRCLE('',#736,2.);
#738=EDGE_CURVE('E356',#706,#730,#737,.T.);
#739=ORIENTED_EDGE('',*,*,#738,.F.);
#740=EDGE_LOOP('',(#708,#716,#724,#732,#739));
#741=FACE_BOUND('',#740,.T.);
#742=ORIENTED_EDGE('',*,*,#60,.F.);
#743=ORIENTED_EDGE('',*,*,#331,.F.);
#744=ORIENTED_EDGE('',*,*,#291,.F.);
#745=ORIENTED_EDGE('',*,*,#238,.F.);
#746=ORIENTED_EDGE('',*,*,#196,.F.);
#747=ORIENTED_EDGE('',*,*,#165,.F.);
#748=ORIENTED_EDGE('',*,*,#120,.F.);
#749=EDGE_LOOP('',(#742,#743,#744,#745,#746,#747,#748));
#750=FACE_BOUND('',#749,.T.);
#751=ADVANCED_FACE('F259',(#595,#698,#741,#750),#552,.F.);
#752=CARTESIAN_POINT('',(80.,9.99999999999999,-70.));
#753=DIRECTION('',(-1.,0.,0.));
#754=DIRECTION('',(0.,0.,1.));
#755=AXIS2_PLACEMENT_3D('',#752,#753,#754);
#756=CYLINDRICAL_SURFACE('',#755,3.25000000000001);
#757=ORIENTED_EDGE('',*,*,#99,.T.);
#758=EDGE_LOOP('',(#757));
#759=FACE_BOUND('',#758,.T.);
#760=ORIENTED_EDGE('',*,*,#323,.F.);
#761=EDGE_LOOP('',(#760));
#762=FACE_BOUND('',#761,.T.);
#763=ADVANCED_FACE('F545',(#759,#762),#756,.F.);
#764=CARTESIAN_POINT('',(80.,9.99999999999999,-50.));
#765=DIRECTION('',(-1.,0.,0.));
#766=DIRECTION('',(0.,0.,1.));
#767=AXIS2_PLACEMENT_3D('',#764,#765,#766);
#768=CYLINDRICAL_SURFACE('',#767,3.25);
#769=CARTESIAN_POINT('',(4.91656822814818,9.99999999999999,-50.));
#770=DIRECTION('',(-1.,0.,0.));
#771=DIRECTION('',(0.,0.,1.));
#772=AXIS2_PLACEMENT_3D('',#769,#770,#771);
#773=CIRCLE('',#772,3.25);
#774=CARTESIAN_POINT('',(4.91656822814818,9.99999999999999,-46.75));
#775=VERTEX_POINT('',#774);
#776=EDGE_CURVE('E381',#775,#775,#773,.F.);
#777=ORIENTED_EDGE('',*,*,#776,.T.);
#778=EDGE_LOOP('',(#777));
#779=FACE_BOUND('',#778,.T.);
#780=ORIENTED_EDGE('',*,*,#110,.T.);
#781=EDGE_LOOP('',(#780));
#782=FACE_BOUND('',#781,.T.);
#783=ADVANCED_FACE('F544',(#779,#782),#768,.F.);
#784=CARTESIAN_POINT('',(70.,10.,-80.));
#785=DIRECTION('',(0.,0.,1.));
#786=DIRECTION('',(1.,0.,0.));
#787=AXIS2_PLACEMENT_3D('',#784,#785,#786);
#788=CYLINDRICAL_SURFACE('',#787,3.25000000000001);
#789=ORIENTED_EDGE('',*,*,#152,.T.);
#790=EDGE_LOOP('',(#789));
#791=FACE_BOUND('',#790,.T.);
#792=ORIENTED_EDGE('',*,*,#228,.F.);
#793=EDGE_LOOP('',(#792));
#794=FACE_BOUND('',#793,.T.);
#795=ADVANCED_FACE('F537',(#791,#794),#788,.F.);
#796=CARTESIAN_POINT('',(56.7965557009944,20.,-5.10542486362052));
#797=DIRECTION('',(0.,0.,1.));
#798=DIRECTION('',(1.,0.,0.));
#799=AXIS2_PLACEMENT_3D('',#796,#797,#798);
#800=PLANE('',#799);
#801=ORIENTED_EDGE('',*,*,#577,.T.);
#802=DIRECTION('',(0.,-1.,0.));
#803=VECTOR('',#802,1.);
#804=CARTESIAN_POINT('',(40.6627812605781,20.,-5.10542486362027));
#805=LINE('',#804,#803);
#806=EDGE_CURVE('E261',#354,#568,#805,.T.);
#807=ORIENTED_EDGE('',*,*,#806,.F.);
#808=ORIENTED_EDGE('',*,*,#388,.F.);
#809=DIRECTION('',(0.,-1.,0.));
#810=VECTOR('',#809,1.);
#811=CARTESIAN_POINT('',(56.7965557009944,20.,-5.10542486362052));
#812=LINE('',#811,#810);
#813=EDGE_CURVE('E262',#381,#576,#812,.T.);
#814=ORIENTED_EDGE('',*,*,#813,.T.);
#815=EDGE_LOOP('',(#801,#807,#808,#814));
#816=FACE_BOUND('',#815,.T.);
#817=ORIENTED_EDGE('',*,*,#31,.F.);
#818=EDGE_LOOP('',(#817));
#819=FACE_BOUND('',#818,.T.);
#820=ADVANCED_FACE('F642',(#816,#819),#800,.F.);
#821=CARTESIAN_POINT('',(35.3190252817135,20.,-31.4113824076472));
#822=DIRECTION('',(0.707106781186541,0.,-0.707106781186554));
#823=DIRECTION('',(-0.707106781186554,0.,-0.707106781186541));
#824=AXIS2_PLACEMENT_3D('',#821,#822,#823);
#825=PLANE('',#824);
#826=CARTESIAN_POINT('',(50.,10.,-16.730407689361));
#827=DIRECTION('',(0.707106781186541,0.,-0.707106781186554));
#828=DIRECTION('',(-0.707106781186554,0.,-0.707106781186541));
#829=AXIS2_PLACEMENT_3D('',#826,#827,#828);
#830=ELLIPSE('',#829,7.77817459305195,5.5);
#831=CARTESIAN_POINT('',(44.5,10.,-22.2304076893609));
#832=VERTEX_POINT('',#831);
#833=EDGE_CURVE('E447',#832,#832,#830,.F.);
#834=ORIENTED_EDGE('',*,*,#833,.F.);
#835=EDGE_LOOP('',(#834));
#836=FACE_BOUND('',#835,.T.);
#837=ORIENTED_EDGE('',*,*,#592,.T.);
#838=DIRECTION('',(0.,-1.,0.));
#839=VECTOR('',#838,1.);
#840=CARTESIAN_POINT('',(58.2107692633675,20.,-8.51963842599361));
#841=LINE('',#840,#839);
#842=EDGE_CURVE('E310',#372,#585,#841,.T.);
#843=ORIENTED_EDGE('',*,*,#842,.F.);
#844=ORIENTED_EDGE('',*,*,#373,.F.);
#845=DIRECTION('',(0.,-1.,0.));
#846=VECTOR('',#845,1.);
#847=CARTESIAN_POINT('',(35.3190252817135,20.,-31.4113824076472));
#848=LINE('',#847,#846);
#849=EDGE_CURVE('E304',#364,#560,#848,.T.);
#850=ORIENTED_EDGE('',*,*,#849,.T.);
#851=EDGE_LOOP('',(#837,#843,#844,#850));
#852=FACE_BOUND('',#851,.T.);
#853=ADVANCED_FACE('F658',(#836,#852),#825,.F.);
#854=CARTESIAN_POINT('',(40.6627812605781,20.,-5.10542486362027));
#855=DIRECTION('',(-0.707106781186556,0.,0.707106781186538));
#856=DIRECTION('',(0.707106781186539,0.,0.707106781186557));
#857=AXIS2_PLACEMENT_3D('',#854,#855,#856);
#858=PLANE('',#857);
#859=ORIENTED_EDGE('',*,*,#569,.T.);
#860=DIRECTION('',(0.,-1.,0.));
#861=VECTOR('',#860,1.);
#862=CARTESIAN_POINT('',(24.8379244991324,20.,-20.9302816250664));
#863=LINE('',#862,#861);
#864=EDGE_CURVE('E301',#356,#558,#863,.T.);
#865=ORIENTED_EDGE('',*,*,#864,.F.);
#866=ORIENTED_EDGE('',*,*,#357,.F.);
#867=ORIENTED_EDGE('',*,*,#806,.T.);
#868=EDGE_LOOP('',(#859,#865,#866,#867));
#869=FACE_BOUND('',#868,.T.);
#870=ADVANCED_FACE('F667',(#869),#858,.F.);
#871=CARTESIAN_POINT('',(56.7965557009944,20.,-7.10542486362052));
#872=DIRECTION('',(0.,-1.,0.));
#873=DIRECTION('',(0.,0.,-1.));
#874=AXIS2_PLACEMENT_3D('',#871,#872,#873);
#875=CYLINDRICAL_SURFACE('',#874,2.);
#876=ORIENTED_EDGE('',*,*,#586,.T.);
#877=ORIENTED_EDGE('',*,*,#813,.F.);
#878=ORIENTED_EDGE('',*,*,#382,.F.);
#879=ORIENTED_EDGE('',*,*,#842,.T.);
#880=EDGE_LOOP('',(#876,#877,#878,#879));
#881=FACE_BOUND('',#880,.T.);
#882=ADVANCED_FACE('F676',(#881),#875,.F.);
#883=CARTESIAN_POINT('',(24.8379244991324,20.,-20.9302816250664));
#884=DIRECTION('',(-0.707106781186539,0.,-0.707106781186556));
#885=DIRECTION('',(-0.707106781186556,0.,0.707106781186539));
#886=AXIS2_PLACEMENT_3D('',#883,#884,#885);
#887=PLANE('',#886);
#888=ORIENTED_EDGE('',*,*,#561,.T.);
#889=ORIENTED_EDGE('',*,*,#849,.F.);
#890=ORIENTED_EDGE('',*,*,#365,.F.);
#891=ORIENTED_EDGE('',*,*,#864,.T.);
#892=EDGE_LOOP('',(#888,#889,#890,#891));
#893=FACE_BOUND('',#892,.T.);
#894=ADVANCED_FACE('F689',(#893),#887,.F.);
#895=CARTESIAN_POINT('',(31.1919343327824,20.,-35.3812399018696));
#896=DIRECTION('',(0.707106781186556,0.,-0.707106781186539));
#897=DIRECTION('',(-0.707106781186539,0.,-0.707106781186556));
#898=AXIS2_PLACEMENT_3D('',#895,#896,#897);
#899=PLANE('',#898);
#900=CARTESIAN_POINT('',(16.5731742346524,9.99999999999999,-50.));
#901=DIRECTION('',(0.707106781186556,0.,-0.707106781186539));
#902=DIRECTION('',(0.707106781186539,0.,0.707106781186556));
#903=AXIS2_PLACEMENT_3D('',#900,#901,#902);
#904=ELLIPSE('',#903,7.77817459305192,5.5);
#905=CARTESIAN_POINT('',(22.0731742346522,9.99999999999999,-44.5));
#906=VERTEX_POINT('',#905);
#907=EDGE_CURVE('E44',#906,#906,#904,.T.);
#908=ORIENTED_EDGE('',*,*,#907,.T.);
#909=EDGE_LOOP('',(#908));
#910=FACE_BOUND('',#909,.T.);
#911=ORIENTED_EDGE('',*,*,#731,.T.);
#912=DIRECTION('',(0.,-1.,0.));
#913=VECTOR('',#912,1.);
#914=CARTESIAN_POINT('',(31.1919343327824,20.,-35.3812399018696));
#915=LINE('',#914,#913);
#916=EDGE_CURVE('E367',#527,#722,#915,.T.);
#917=ORIENTED_EDGE('',*,*,#916,.F.);
#918=ORIENTED_EDGE('',*,*,#528,.F.);
#919=DIRECTION('',(0.,-1.,0.));
#920=VECTOR('',#919,1.);
#921=CARTESIAN_POINT('',(8.33078179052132,20.,-58.2423924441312));
#922=LINE('',#921,#920);
#923=EDGE_CURVE('E371',#519,#730,#922,.T.);
#924=ORIENTED_EDGE('',*,*,#923,.T.);
#925=EDGE_LOOP('',(#911,#917,#918,#924));
#926=FACE_BOUND('',#925,.T.);
#927=ADVANCED_FACE('F697',(#910,#926),#899,.F.);
#928=CARTESIAN_POINT('',(4.91656822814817,20.,-56.8281788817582));
#929=DIRECTION('',(-1.,0.,0.));
#930=DIRECTION('',(0.,0.,1.));
#931=AXIS2_PLACEMENT_3D('',#928,#929,#930);
#932=PLANE('',#931);
#933=ORIENTED_EDGE('',*,*,#707,.T.);
#934=DIRECTION('',(0.,-1.,0.));
#935=VECTOR('',#934,1.);
#936=CARTESIAN_POINT('',(4.91656822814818,20.,-56.8281788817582));
#937=LINE('',#936,#935);
#938=EDGE_CURVE('E373',#510,#706,#937,.T.);
#939=ORIENTED_EDGE('',*,*,#938,.F.);
#940=ORIENTED_EDGE('',*,*,#511,.F.);
#941=DIRECTION('',(0.,-1.,0.));
#942=VECTOR('',#941,1.);
#943=CARTESIAN_POINT('',(4.91656822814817,20.,-40.9348925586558));
#944=LINE('',#943,#942);
#945=EDGE_CURVE('E355',#502,#704,#944,.T.);
#946=ORIENTED_EDGE('',*,*,#945,.T.);
#947=EDGE_LOOP('',(#933,#939,#940,#946));
#948=FACE_BOUND('',#947,.T.);
#949=ORIENTED_EDGE('',*,*,#776,.F.);
#950=EDGE_LOOP('',(#949));
#951=FACE_BOUND('',#950,.T.);
#952=ADVANCED_FACE('F708',(#948,#951),#932,.F.);
#953=CARTESIAN_POINT('',(4.91656822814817,20.,-40.9348925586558));
#954=DIRECTION('',(-0.703989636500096,0.,0.710210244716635));
#955=DIRECTION('',(0.710210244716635,0.,0.703989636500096));
#956=AXIS2_PLACEMENT_3D('',#953,#954,#955);
#957=PLANE('',#956);
#958=ORIENTED_EDGE('',*,*,#715,.T.);
#959=ORIENTED_EDGE('',*,*,#945,.F.);
#960=ORIENTED_EDGE('',*,*,#503,.F.);
#961=DIRECTION('',(0.,-1.,0.));
#962=VECTOR('',#961,1.);
#963=CARTESIAN_POINT('',(20.90108039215,20.,-25.0903859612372));
#964=LINE('',#963,#962);
#965=EDGE_CURVE('E366',#500,#714,#964,.T.);
#966=ORIENTED_EDGE('',*,*,#965,.T.);
#967=EDGE_LOOP('',(#958,#959,#960,#966));
#968=FACE_BOUND('',#967,.T.);
#969=ADVANCED_FACE('F719',(#968),#957,.F.);
#970=CARTESIAN_POINT('',(20.90108039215,20.,-25.0903859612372));
#971=DIRECTION('',(0.707106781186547,0.,0.707106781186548));
#972=DIRECTION('',(0.707106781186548,0.,-0.707106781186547));
#973=AXIS2_PLACEMENT_3D('',#970,#971,#972);
#974=PLANE('',#973);
#975=ORIENTED_EDGE('',*,*,#723,.T.);
#976=ORIENTED_EDGE('',*,*,#965,.F.);
#977=ORIENTED_EDGE('',*,*,#534,.F.);
#978=ORIENTED_EDGE('',*,*,#916,.T.);
#979=EDGE_LOOP('',(#975,#976,#977,#978));
#980=FACE_BOUND('',#979,.T.);
#981=ADVANCED_FACE('F728',(#980),#974,.F.);
#982=CARTESIAN_POINT('',(6.91656822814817,20.,-56.8281788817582));
#983=DIRECTION('',(0.,-1.,0.));
#984=DIRECTION('',(0.,0.,-1.));
#985=AXIS2_PLACEMENT_3D('',#982,#983,#984);
#986=CYLINDRICAL_SURFACE('',#985,2.);
#987=ORIENTED_EDGE('',*,*,#738,.T.);
#988=ORIENTED_EDGE('',*,*,#923,.F.);
#989=ORIENTED_EDGE('',*,*,#520,.F.);
#990=ORIENTED_EDGE('',*,*,#938,.T.);
#991=EDGE_LOOP('',(#987,#988,#989,#990));
#992=FACE_BOUND('',#991,.T.);
#993=ADVANCED_FACE('F738',(#992),#986,.F.);
#994=CARTESIAN_POINT('',(12.1608269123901,20.,-5.10542486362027));
#995=DIRECTION('',(-1.,0.,0.));
#996=DIRECTION('',(0.,0.,1.));
#997=AXIS2_PLACEMENT_3D('',#994,#995,#996);
#998=PLANE('',#997);
#999=ORIENTED_EDGE('',*,*,#613,.T.);
#1000=DIRECTION('',(0.,-1.,0.));
#1001=VECTOR('',#1000,1.);
#1002=CARTESIAN_POINT('',(12.1608269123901,20.,-8.24916747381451));
#1003=LINE('',#1002,#1001);
#1004=EDGE_CURVE('E275',#399,#602,#1003,.T.);
#1005=ORIENTED_EDGE('',*,*,#1004,.F.);
#1006=ORIENTED_EDGE('',*,*,#400,.F.);
#1007=DIRECTION('',(0.,-1.,0.));
#1008=VECTOR('',#1007,1.);
#1009=CARTESIAN_POINT('',(12.1608269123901,20.,-5.10542486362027));
#1010=LINE('',#1009,#1008);
#1011=EDGE_CURVE('E231',#397,#612,#1010,.T.);
#1012=ORIENTED_EDGE('',*,*,#1011,.T.);
#1013=EDGE_LOOP('',(#999,#1005,#1006,#1012));
#1014=FACE_BOUND('',#1013,.T.);
#1015=ADVANCED_FACE('F232',(#1014),#998,.F.);
#1016=CARTESIAN_POINT('',(12.1608269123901,20.,-5.10542486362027));
#1017=DIRECTION('',(0.,0.,1.));
#1018=DIRECTION('',(1.,0.,0.));
#1019=AXIS2_PLACEMENT_3D('',#1016,#1017,#1018);
#1020=PLANE('',#1019);
#1021=ORIENTED_EDGE('',*,*,#621,.T.);
#1022=ORIENTED_EDGE('',*,*,#1011,.F.);
#1023=ORIENTED_EDGE('',*,*,#491,.F.);
#1024=DIRECTION('',(0.,-1.,0.));
#1025=VECTOR('',#1024,1.);
#1026=CARTESIAN_POINT('',(28.6513600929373,20.,-5.10542486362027));
#1027=LINE('',#1026,#1025);
#1028=EDGE_CURVE('E242',#484,#620,#1027,.T.);
#1029=ORIENTED_EDGE('',*,*,#1028,.T.);
#1030=EDGE_LOOP('',(#1021,#1022,#1023,#1029));
#1031=FACE_BOUND('',#1030,.T.);
#1032=ADVANCED_FACE('F248',(#1031),#1020,.F.);
#1033=CARTESIAN_POINT('',(28.6513600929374,20.,-7.10542486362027));
#1034=DIRECTION('',(0.,-1.,0.));
#1035=DIRECTION('',(0.,0.,-1.));
#1036=AXIS2_PLACEMENT_3D('',#1033,#1034,#1035);
#1037=CYLINDRICAL_SURFACE('',#1036,2.);
#1038=ORIENTED_EDGE('',*,*,#630,.T.);
#1039=ORIENTED_EDGE('',*,*,#1028,.F.);
#1040=ORIENTED_EDGE('',*,*,#485,.F.);
#1041=DIRECTION('',(0.,-1.,0.));
#1042=VECTOR('',#1041,1.);
#1043=CARTESIAN_POINT('',(30.0655736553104,20.,-8.51963842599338));
#1044=LINE('',#1043,#1042);
#1045=EDGE_CURVE('E476',#475,#629,#1044,.T.);
#1046=ORIENTED_EDGE('',*,*,#1045,.T.);
#1047=EDGE_LOOP('',(#1038,#1039,#1040,#1046));
#1048=FACE_BOUND('',#1047,.T.);
#1049=ADVANCED_FACE('F764',(#1048),#1037,.F.);
#1050=CARTESIAN_POINT('',(30.0655736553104,20.,-8.51963842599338));
#1051=DIRECTION('',(0.707106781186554,0.,-0.707106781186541));
#1052=DIRECTION('',(-0.707106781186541,0.,-0.707106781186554));
#1053=AXIS2_PLACEMENT_3D('',#1050,#1051,#1052);
#1054=PLANE('',#1053);
#1055=ORIENTED_EDGE('',*,*,#638,.T.);
#1056=ORIENTED_EDGE('',*,*,#1045,.F.);
#1057=ORIENTED_EDGE('',*,*,#476,.F.);
#1058=DIRECTION('',(0.,-1.,0.));
#1059=VECTOR('',#1058,1.);
#1060=CARTESIAN_POINT('',(8.33078179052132,20.,-30.2544302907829));
#1061=LINE('',#1060,#1059);
#1062=EDGE_CURVE('E473',#467,#637,#1061,.T.);
#1063=ORIENTED_EDGE('',*,*,#1062,.T.);
#1064=EDGE_LOOP('',(#1055,#1056,#1057,#1063));
#1065=FACE_BOUND('',#1064,.T.);
#1066=ADVANCED_FACE('F771',(#1065),#1054,.F.);
#1067=CARTESIAN_POINT('',(6.91656822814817,20.,-28.8402167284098));
#1068=DIRECTION('',(0.,-1.,0.));
#1069=DIRECTION('',(0.,0.,-1.));
#1070=AXIS2_PLACEMENT_3D('',#1067,#1068,#1069);
#1071=CYLINDRICAL_SURFACE('',#1070,2.);
#1072=ORIENTED_EDGE('',*,*,#647,.T.);
#1073=ORIENTED_EDGE('',*,*,#1062,.F.);
#1074=ORIENTED_EDGE('',*,*,#468,.F.);
#1075=DIRECTION('',(0.,-1.,0.));
#1076=VECTOR('',#1075,1.);
#1077=CARTESIAN_POINT('',(4.91656822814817,20.,-28.8402167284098));
#1078=LINE('',#1077,#1076);
#1079=EDGE_CURVE('E471',#458,#646,#1078,.T.);
#1080=ORIENTED_EDGE('',*,*,#1079,.T.);
#1081=EDGE_LOOP('',(#1072,#1073,#1074,#1080));
#1082=FACE_BOUND('',#1081,.T.);
#1083=ADVANCED_FACE('F783',(#1082),#1071,.F.);
#1084=CARTESIAN_POINT('',(4.91656822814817,20.,-28.8402167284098));
#1085=DIRECTION('',(-1.,0.,0.));
#1086=DIRECTION('',(0.,0.,1.));
#1087=AXIS2_PLACEMENT_3D('',#1084,#1085,#1086);
#1088=PLANE('',#1087);
#1089=ORIENTED_EDGE('',*,*,#655,.T.);
#1090=ORIENTED_EDGE('',*,*,#1079,.F.);
#1091=ORIENTED_EDGE('',*,*,#459,.F.);
#1092=DIRECTION('',(0.,-1.,0.));
#1093=VECTOR('',#1092,1.);
#1094=CARTESIAN_POINT('',(4.91656822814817,20.,-12.0905084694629));
#1095=LINE('',#1094,#1093);
#1096=EDGE_CURVE('E468',#450,#654,#1095,.T.);
#1097=ORIENTED_EDGE('',*,*,#1096,.T.);
#1098=EDGE_LOOP('',(#1089,#1090,#1091,#1097));
#1099=FACE_BOUND('',#1098,.T.);
#1100=ADVANCED_FACE('F794',(#1099),#1088,.F.);
#1101=CARTESIAN_POINT('',(4.91656822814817,20.,-12.0905084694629));
#1102=DIRECTION('',(0.,0.,1.));
#1103=DIRECTION('',(1.,0.,0.));
#1104=AXIS2_PLACEMENT_3D('',#1101,#1102,#1103);
#1105=PLANE('',#1104);
#1106=ORIENTED_EDGE('',*,*,#663,.T.);
#1107=ORIENTED_EDGE('',*,*,#1096,.F.);
#1108=ORIENTED_EDGE('',*,*,#451,.F.);
#1109=DIRECTION('',(0.,-1.,0.));
#1110=VECTOR('',#1109,1.);
#1111=CARTESIAN_POINT('',(8.00052028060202,20.,-12.0905084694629));
#1112=LINE('',#1111,#1110);
#1113=EDGE_CURVE('E466',#442,#662,#1112,.T.);
#1114=ORIENTED_EDGE('',*,*,#1113,.T.);
#1115=EDGE_LOOP('',(#1106,#1107,#1108,#1114));
#1116=FACE_BOUND('',#1115,.T.);
#1117=ADVANCED_FACE('F803',(#1116),#1105,.F.);
#1118=CARTESIAN_POINT('',(12.1608269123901,20.,-12.4227167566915));
#1119=DIRECTION('',(0.,-1.,0.));
#1120=DIRECTION('',(0.,0.,-1.));
#1121=AXIS2_PLACEMENT_3D('',#1118,#1119,#1120);
#1122=CYLINDRICAL_SURFACE('',#1121,4.17354928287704);
#1123=ORIENTED_EDGE('',*,*,#672,.T.);
#1124=ORIENTED_EDGE('',*,*,#1113,.F.);
#1125=ORIENTED_EDGE('',*,*,#443,.F.);
#1126=DIRECTION('',(0.,-1.,0.));
#1127=VECTOR('',#1126,1.);
#1128=CARTESIAN_POINT('',(14.030107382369,20.,-16.1542451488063));
#1129=LINE('',#1128,#1127);
#1130=EDGE_CURVE('E467',#433,#671,#1129,.T.);
#1131=ORIENTED_EDGE('',*,*,#1130,.T.);
#1132=EDGE_LOOP('',(#1123,#1124,#1125,#1131));
#1133=FACE_BOUND('',#1132,.T.);
#1134=ADVANCED_FACE('F815',(#1133),#1122,.T.);
#1135=CARTESIAN_POINT('',(12.6254849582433,20.,-14.4302689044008));
#1136=DIRECTION('',(-0.775256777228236,0.,-0.631646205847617));
#1137=DIRECTION('',(-0.631646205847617,0.,0.775256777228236));
#1138=AXIS2_PLACEMENT_3D('',#1135,#1136,#1137);
#1139=PLANE('',#1138);
#1140=ORIENTED_EDGE('',*,*,#680,.T.);
#1141=ORIENTED_EDGE('',*,*,#1130,.F.);
#1142=ORIENTED_EDGE('',*,*,#434,.F.);
#1143=DIRECTION('',(0.,-1.,0.));
#1144=VECTOR('',#1143,1.);
#1145=CARTESIAN_POINT('',(12.6254849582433,20.,-14.4302689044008));
#1146=LINE('',#1145,#1144);
#1147=EDGE_CURVE('E461',#425,#679,#1146,.T.);
#1148=ORIENTED_EDGE('',*,*,#1147,.T.);
#1149=EDGE_LOOP('',(#1140,#1141,#1142,#1148));
#1150=FACE_BOUND('',#1149,.T.);
#1151=ADVANCED_FACE('F822',(#1150),#1139,.F.);
#1152=CARTESIAN_POINT('',(12.1608269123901,20.,-12.4227167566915));
#1153=DIRECTION('',(0.,-1.,0.));
#1154=DIRECTION('',(0.,0.,-1.));
#1155=AXIS2_PLACEMENT_3D('',#1152,#1153,#1154);
#1156=CYLINDRICAL_SURFACE('',#1155,2.06062435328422);
#1157=ORIENTED_EDGE('',*,*,#689,.T.);
#1158=ORIENTED_EDGE('',*,*,#1147,.F.);
#1159=ORIENTED_EDGE('',*,*,#426,.F.);
#1160=DIRECTION('',(0.,-1.,0.));
#1161=VECTOR('',#1160,1.);
#1162=CARTESIAN_POINT('',(14.2026570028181,20.,-12.7003903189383));
#1163=LINE('',#1162,#1161);
#1164=EDGE_CURVE('E464',#416,#688,#1163,.T.);
#1165=ORIENTED_EDGE('',*,*,#1164,.T.);
#1166=EDGE_LOOP('',(#1157,#1158,#1159,#1165));
#1167=FACE_BOUND('',#1166,.T.);
#1168=ADVANCED_FACE('F510',(#1167),#1156,.F.);
#1169=CARTESIAN_POINT('',(16.0655128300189,20.,-13.8964675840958));
#1170=DIRECTION('',(0.540286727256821,0.,0.841480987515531));
#1171=DIRECTION('',(0.841480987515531,0.,-0.540286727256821));
#1172=AXIS2_PLACEMENT_3D('',#1169,#1170,#1171);
#1173=PLANE('',#1172);
#1174=ORIENTED_EDGE('',*,*,#695,.T.);
#1175=ORIENTED_EDGE('',*,*,#1164,.F.);
#1176=ORIENTED_EDGE('',*,*,#417,.F.);
#1177=DIRECTION('',(0.,-1.,0.));
#1178=VECTOR('',#1177,1.);
#1179=CARTESIAN_POINT('',(16.0655128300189,20.,-13.8964675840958));
#1180=LINE('',#1179,#1178);
#1181=EDGE_CURVE('E459',#408,#604,#1180,.T.);
#1182=ORIENTED_EDGE('',*,*,#1181,.T.);
#1183=EDGE_LOOP('',(#1174,#1175,#1176,#1182));
#1184=FACE_BOUND('',#1183,.T.);
#1185=ADVANCED_FACE('F505',(#1184),#1173,.F.);
#1186=CARTESIAN_POINT('',(12.1608269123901,20.,-12.4227167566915));
#1187=DIRECTION('',(0.,-1.,0.));
#1188=DIRECTION('',(0.,0.,-1.));
#1189=AXIS2_PLACEMENT_3D('',#1186,#1187,#1188);
#1190=CYLINDRICAL_SURFACE('',#1189,4.17354928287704);
#1191=ORIENTED_EDGE('',*,*,#605,.T.);
#1192=ORIENTED_EDGE('',*,*,#1181,.F.);
#1193=ORIENTED_EDGE('',*,*,#409,.F.);
#1194=ORIENTED_EDGE('',*,*,#1004,.T.);
#1195=EDGE_LOOP('',(#1191,#1192,#1193,#1194));
#1196=FACE_BOUND('',#1195,.T.);
#1197=ADVANCED_FACE('F511',(#1196),#1190,.T.);
#1198=CARTESIAN_POINT('',(50.,10.,-10.));
#1199=DIRECTION('',(0.,0.,-1.));
#1200=DIRECTION('',(-1.,0.,0.));
#1201=AXIS2_PLACEMENT_3D('',#1198,#1199,#1200);
#1202=CYLINDRICAL_SURFACE('',#1201,5.5);
#1203=ORIENTED_EDGE('',*,*,#833,.T.);
#1204=EDGE_LOOP('',(#1203));
#1205=FACE_BOUND('',#1204,.T.);
#1206=ORIENTED_EDGE('',*,*,#281,.T.);
#1207=EDGE_LOOP('',(#1206));
#1208=FACE_BOUND('',#1207,.T.);
#1209=ADVANCED_FACE('F519',(#1205,#1208),#1202,.F.);
#1210=CARTESIAN_POINT('',(10.,9.99999999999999,-50.));
#1211=DIRECTION('',(1.,0.,0.));
#1212=DIRECTION('',(0.,0.,-1.));
#1213=AXIS2_PLACEMENT_3D('',#1210,#1211,#1212);
#1214=CYLINDRICAL_SURFACE('',#1213,5.5);
#1215=ORIENTED_EDGE('',*,*,#907,.F.);
#1216=EDGE_LOOP('',(#1215));
#1217=FACE_BOUND('',#1216,.T.);
#1218=ORIENTED_EDGE('',*,*,#270,.F.);
#1219=EDGE_LOOP('',(#1218));
#1220=FACE_BOUND('',#1219,.T.);
#1221=ADVANCED_FACE('F522',(#1217,#1220),#1214,.F.);
#1222=CLOSED_SHELL('',(#46,#86,#139,#184,#215,#257,#310,#343,#547,#751,#763,#783,#795,#820,#853,
#870,#882,#894,#927,#952,#969,#981,#993,#1015,#1032,#1049,#1066,#1083,#1100,#1117,#1134,#1151,
#1168,#1185,#1197,#1209,#1221));
#1223=MANIFOLD_SOLID_BREP('B2',#1222);
#1224=ADVANCED_BREP_SHAPE_REPRESENTATION('',(#18,#1223),#14);
#1225=SHAPE_DEFINITION_REPRESENTATION(#9,#1224);
ENDSEC;
END-ISO-10303-21;
